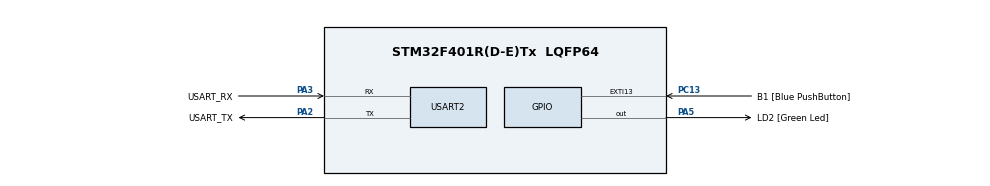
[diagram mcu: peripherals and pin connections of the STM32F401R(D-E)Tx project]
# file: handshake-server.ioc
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Mcu.Family=STM32F4
Mcu.Name=STM32F401R(D-E)Tx
Mcu.Package=LQFP64
NVIC.PriorityGroup=NVIC_PRIORITYGROUP_4
NVIC.USART2_IRQn=true\:0\:0\:false\:false\:true\:true\:true\:true
PA13.GPIO_Label=TMS
PA13.Mode=Trace_Asynchronous_SW
PA13.Signal=SYS_JTMS-SWDIO
PA14.GPIO_Label=TCK
PA14.Mode=Trace_Asynchronous_SW
PA14.Signal=SYS_JTCK-SWCLK
PA2.GPIO_Label=USART_TX
PA2.GPIO_Mode=GPIO_MODE_AF_PP
PA2.GPIO_PuPd=GPIO_NOPULL
PA2.GPIO_Speed=GPIO_SPEED_FREQ_LOW
PA2.Mode=Asynchronous
PA2.Signal=USART2_TX
PA3.GPIO_Label=USART_RX
PA3.GPIO_Mode=GPIO_MODE_AF_PP
PA3.GPIO_PuPd=GPIO_NOPULL
PA3.GPIO_Speed=GPIO_SPEED_FREQ_LOW
PA3.Mode=Asynchronous
PA3.Signal=USART2_RX
PA5.GPIO_Label=LD2 [Green Led]
PA5.GPIO_Mode=GPIO_MODE_OUTPUT_PP
PA5.GPIO_PuPd=GPIO_NOPULL
PA5.GPIO_Speed=GPIO_SPEED_FREQ_LOW
PA5.Signal=GPIO_Output
PB3.GPIO_Label=SWO
PB3.Mode=Trace_Asynchronous_SW
PB3.Signal=SYS_JTDO-SWO
PC13-ANTI_TAMP.GPIO_Label=B1 [Blue PushButton]
PC13-ANTI_TAMP.GPIO_ModeDefaultEXTI=GPIO_MODE_IT_FALLING
PC13-ANTI_TAMP.GPIO_PuPd=GPIO_NOPULL
PC13-ANTI_TAMP.Signal=GPXTI13
PC14-OSC32_IN.Mode=LSE-External-Oscillator
PC14-OSC32_IN.Signal=RCC_OSC32_IN
PC15-OSC32_OUT.Mode=LSE-External-Oscillator
PC15-OSC32_OUT.Signal=RCC_OSC32_OUT
PH0\ -\ OSC_IN.Mode=HSE-External-Clock-Source
PH0\ -\ OSC_IN.Signal=RCC_OSC_IN
PH1\ -\ OSC_OUT.Mode=HSE-External-Clock-Source
PH1\ -\ OSC_OUT.Signal=RCC_OSC_OUT
ProjectManager.HeapSize=0x200
ProjectManager.StackSize=0x400
ProjectManager.TargetToolchain=Makefile
RCC.48MHZClocksFreq_Value=48000000
RCC.AHBFreq_Value=84000000
RCC.APB1CLKDivider=RCC_HCLK_DIV2
RCC.APB1Freq_Value=42000000
RCC.APB1TimFreq_Value=84000000
RCC.APB2Freq_Value=84000000
RCC.APB2TimFreq_Value=84000000
RCC.CortexFreq_Value=84000000
RCC.HCLKFreq_Value=84000000
RCC.HSE_VALUE=8000000
RCC.HSI_VALUE=16000000
RCC.PLLN=336
RCC.PLLP=RCC_PLLP_DIV4
RCC.PLLQ=7
RCC.SYSCLKFreq_VALUE=84000000
RCC.SYSCLKSource=RCC_SYSCLKSOURCE_PLLCLK
RCC.VCOOutputFreq_Value=336000000
USART2.VirtualMode=VM_ASYNC
board=NUCLEO-F401RE

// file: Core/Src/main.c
/* USER CODE BEGIN Header */
/**
  ******************************************************************************
  * @file           : main.c
  * @brief          : Main program body
  ******************************************************************************
  * @attention
  *
  * Copyright (c) 2025 STMicroelectronics.
  * All rights reserved.
  *
  * This software is licensed under terms that can be found in the LICENSE file
  * in the root directory of this software component.
  * If no LICENSE file comes with this software, it is provided AS-IS.
  *
  ******************************************************************************
  */
/* USER CODE END Header */
#include "main.h"
#include "usart.h"
#include "gpio.h"

/* USER CODE BEGIN Includes */
#include "packet.h"
/* USER CODE END Includes */

/* USER CODE BEGIN PV */
packet_t tx_packet, rx_packet;
uint8_t rx_buffer[4], tx_buffer[4];
uint8_t echo_buffer[16] = {'\0'}; // for ECHO
// Microcontroller acts as a verifier
// PC sends a request, board evaluates it and has 3 outcomes:
// SUCCESS: send
// >> PC will send a packet verifying the success packet
// >> Switch to echo mode
// INVALID_HEADER:
// >> Send error packet
// INVALID_CHECKSUM:
// >> Send error packet

// 'S' for success and 'E' for error
// 0, 1 codes for syn, ack (for success) and header, checksum errors
char syn_success[2] = {'S', 0};
char ack_success[2] = {'S', 1};
char inv_header[2]  = {'E', 0};
char inv_cksum[2]   = {'E', 1};

comm_status phase = COMM_NOT_INIT;
/* USER CODE END PV */

void SystemClock_Config(void);

int main(void)
{

  /* USER CODE BEGIN 1 */
  tx_packet.header = 28;
  /* USER CODE END 1 */

  /* MCU Configuration--------------------------------------------------------*/

  /* Reset of all peripherals, Initializes the Flash interface and the Systick. */
  HAL_Init();

  /* Configure the system clock */
  SystemClock_Config();

  /* Initialize all configured peripherals */
  MX_GPIO_Init();
  MX_USART2_UART_Init();
  /* USER CODE BEGIN 2 */

  // Echo
  // HAL_UART_Receive_IT(&huart2, echo_buffer, sizeof(echo_buffer));

  // HANDSHAKE
  HAL_UART_Receive_IT(&huart2, rx_buffer, sizeof(packet_t));

  /* USER CODE END 2 */

  /* Infinite loop */
  while (1)
  {

  }
}

void SystemClock_Config(void)
{
  RCC_OscInitTypeDef RCC_OscInitStruct = {0};
  RCC_ClkInitTypeDef RCC_ClkInitStruct = {0};

  /** Configure the main internal regulator output voltage
  */
  __HAL_RCC_PWR_CLK_ENABLE();
  __HAL_PWR_VOLTAGESCALING_CONFIG(PWR_REGULATOR_VOLTAGE_SCALE2);

  /** Initializes the RCC Oscillators according to the specified parameters
  * in the RCC_OscInitTypeDef structure.
  */
  RCC_OscInitStruct.OscillatorType = RCC_OSCILLATORTYPE_HSI;
  RCC_OscInitStruct.HSIState = RCC_HSI_ON;
  RCC_OscInitStruct.HSICalibrationValue = RCC_HSICALIBRATION_DEFAULT;
  RCC_OscInitStruct.PLL.PLLState = RCC_PLL_NONE;
  if (HAL_RCC_OscConfig(&RCC_OscInitStruct) != HAL_OK)
  {
    Error_Handler();
  }

  /** Initializes the CPU, AHB and APB buses clocks
  */
  RCC_ClkInitStruct.ClockType = RCC_CLOCKTYPE_HCLK|RCC_CLOCKTYPE_SYSCLK
                              |RCC_CLOCKTYPE_PCLK1|RCC_CLOCKTYPE_PCLK2;
  RCC_ClkInitStruct.SYSCLKSource = RCC_SYSCLKSOURCE_HSI;
  RCC_ClkInitStruct.AHBCLKDivider = RCC_SYSCLK_DIV1;
  RCC_ClkInitStruct.APB1CLKDivider = RCC_HCLK_DIV1;
  RCC_ClkInitStruct.APB2CLKDivider = RCC_HCLK_DIV1;

  if (HAL_RCC_ClockConfig(&RCC_ClkInitStruct, FLASH_LATENCY_0) != HAL_OK)
  {
    Error_Handler();
  }
}

/* USER CODE BEGIN 4 */

void HAL_UART_TxCpltCallback(UART_HandleTypeDef *huart){
  if(huart == &huart2){
    if (phase == ECHO_MODE) {
      HAL_UART_Receive_IT(&huart2, echo_buffer, sizeof(echo_buffer)); // for echo
    } else {
      HAL_UART_Receive_IT(&huart2, rx_buffer, sizeof(rx_buffer));     // for handshake
    }
  }
}

void HAL_UART_RxCpltCallback(UART_HandleTypeDef *huart){
  p_status status;
  // not used, but we can make a use case later on
  char msg[2];
  if (huart == &huart2) {
    // ECHO MODE
    if (phase == ECHO_MODE) {
        // Just echo back what was received
        HAL_UART_Transmit_IT(&huart2, echo_buffer, sizeof(echo_buffer));
        return;
    } else {

    // HANDSHAKE MODE, comment the block if you don't want the handshake
    buffer_to_packet(&rx_packet, rx_buffer);
    status = unpack(rx_packet, msg);

    switch (status) {
      case PACKET_VALID:
        switch (phase) {
          case COMM_NOT_INIT:
            prepare_packet(&tx_packet, syn_success);
            phase = COMM_IN_PROGRESS;
            break;
          case COMM_IN_PROGRESS:
            prepare_packet(&tx_packet, ack_success);
            phase = ECHO_MODE;
            break;
          case ECHO_MODE:
            // Echo mode is handled above
            break;
          default:
            break;
        }
        break;

      case INVALID_HEADER:
        prepare_packet(&tx_packet, inv_header);
        phase = COMM_NOT_INIT;
        break;
      case INVALID_CHECKSUM:
        prepare_packet(&tx_packet, inv_cksum);
        phase = COMM_NOT_INIT;
        break;
      default:
        break;
    }
    packet_to_buffer(tx_packet, tx_buffer);
    HAL_UART_Transmit_IT(&huart2, tx_buffer, sizeof(packet_t));
    }
  }
}

/* USER CODE END 4 */

void Error_Handler(void)
{
  __disable_irq();
  while (1)
  {
  }
}
